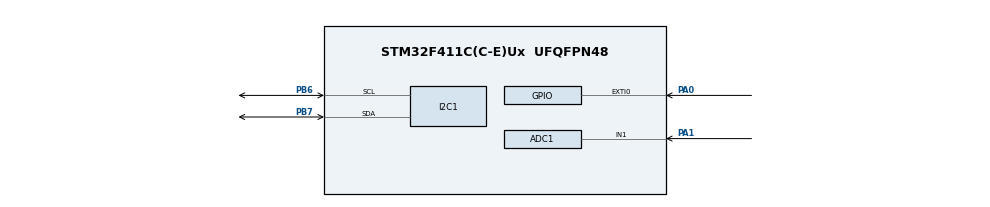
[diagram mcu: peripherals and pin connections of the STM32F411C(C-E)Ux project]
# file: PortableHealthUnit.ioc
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ADC1.Channel-0\#ChannelRegularConversion=ADC_CHANNEL_1
ADC1.NbrOfConversionFlag=1
ADC1.Rank-0\#ChannelRegularConversion=1
ADC1.SamplingTime-0\#ChannelRegularConversion=ADC_SAMPLETIME_3CYCLES
ADC1.master=1
Mcu.Family=STM32F4
Mcu.Name=STM32F411C(C-E)Ux
Mcu.Package=UFQFPN48
NVIC.PriorityGroup=NVIC_PRIORITYGROUP_4
PA0-WKUP.Signal=GPXTI0
PA1.Signal=ADCx_IN1
PB6.Mode=I2C
PB6.Signal=I2C1_SCL
PB7.Mode=I2C
PB7.Signal=I2C1_SDA
ProjectManager.HeapSize=0x200
ProjectManager.StackSize=0x400
ProjectManager.TargetToolchain=STM32CubeIDE
RCC.48MHZClocksFreq_Value=48000000
RCC.AHBFreq_Value=16000000
RCC.APB1Freq_Value=16000000
RCC.APB1TimFreq_Value=16000000
RCC.APB2Freq_Value=16000000
RCC.APB2TimFreq_Value=16000000
RCC.CortexFreq_Value=16000000
RCC.HCLKFreq_Value=16000000
RCC.HSE_VALUE=25000000
RCC.HSI_VALUE=16000000
RCC.LSE_VALUE=32768
RCC.SYSCLKFreq_VALUE=16000000
RCC.VCOOutputFreq_Value=192000000
SH.ADCx_IN1.0=ADC1_IN1,IN1
board=custom

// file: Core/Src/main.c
#include "main.h"
#include "i2c_lcd.h"
// #include "max30102.h" // MAX30102 header commented out
#include <stdio.h>

ADC_HandleTypeDef hadc1;
I2C_HandleTypeDef hi2c1;

// max30102_t max30102; // MAX30102 handle commented out

void SystemClock_Config(void);
static void MX_GPIO_Init(void);
static void MX_I2C1_Init(void);
static void MX_ADC1_Init(void);

int main(void)
{
  HAL_Init();
  SystemClock_Config();
  MX_GPIO_Init();
  MX_I2C1_Init();
  MX_ADC1_Init(); // Initialize the ADC

  lcd_init();
  // max30102_init(&max30102, &hi2c1); // MAX30102 init commented out

  lcd_clear();
  lcd_send_string("Reading Temp...");

  // char hr_str[20];     // MAX30102 string commented out
  // char spo2_str[20];   // MAX30102 string commented out
  char temp_str[20];

  uint32_t adc_value;
  float temperature_c;

  while (1)
  {
    // --- Read Temperature from LM35 ---
    HAL_ADC_Start(&hadc1);
    if (HAL_ADC_PollForConversion(&hadc1, 1000) == HAL_OK)
    {
        adc_value = HAL_ADC_GetValue(&hadc1);
        // Convert ADC value to voltage (assuming V_REF = 3.3V, ADC is 12-bit)
        // Then convert voltage to temperature (LM35 is 10mV/°C)
        temperature_c = ((float)adc_value / 4095.0) * 330.0;
    }tht
    HAL_ADC_Stop(&hadc1);

    // --- MAX30102 reading logic commented out ---
    // max30102_read_fifo(&max30102);
    // max30102_update(&max30102);

    // --- Update the LCD Display ---
    lcd_clear();

    // --- Displaying HR and SpO2 commented out ---
    /*
    sprintf(hr_str, "HR: %.0f BPM", max30102.heart_rate);
    sprintf(spo2_str, "SpO2: %.0f %%", max30102.spO2);
    lcd_put_cur(0, 0);
    lcd_send_string(hr_str);
    lcd_put_cur(1, 0);
    lcd_send_string(spo2_str);
    */

    // Format and display Temperature
    sprintf(temp_str, "Temp: %.2f C", temperature_c);
    lcd_put_cur(0, 0); // Display on the first line
    lcd_send_string(temp_str);

    HAL_Delay(1000); // Update display every second
  }
}

// ... (Your SystemClock_Config, MX_GPIO_Init, and MX_I2C1_Init functions) ...

static void MX_ADC1_Init(void)
{
  ADC_ChannelConfTypeDef sConfig = {0};

  hadc1.Instance = ADC1;
  hadc1.Init.ClockPrescaler = ADC_CLOCK_SYNC_PCLK_DIV4;
  hadc1.Init.Resolution = ADC_RESOLUTION_12B;
  hadc1.Init.ScanConvMode = DISABLE;
  hadc1.Init.ContinuousConvMode = DISABLE;
  hadc1.Init.DiscontinuousConvMode = DISABLE;
  hadc1.Init.ExternalTrigConvEdge = ADC_EXTERNALTRIGCONVEDGE_NONE;
  hadc1.Init.ExternalTrigConv = ADC_SOFTWARE_START;
  hadc1.Init.DataAlign = ADC_DATAALIGN_RIGHT;
  hadc1.Init.NbrOfConversion = 1;
  hadc1.Init.DMAContinuousRequests = DISABLE;
  hadc1.Init.EOCSelection = ADC_EOC_SINGLE_CONV;
  if (HAL_ADC_Init(&hadc1) != HAL_OK)
  {
    Error_Handler();
  }

  sConfig.Channel = ADC_CHANNEL_1;
  sConfig.Rank = 1;
  sConfig.SamplingTime = ADC_SAMPLETIME_3CYCLES;
  if (HAL_ADC_ConfigChannel(&hadc1, &sConfig) != HAL_OK)
  {
    Error_Handler();
  }
}

void SystemClock_Config(void)
{
  RCC_OscInitTypeDef RCC_OscInitStruct = {0};
  RCC_ClkInitTypeDef RCC_ClkInitStruct = {0};

  /** Configure the main internal regulator output voltage
  */
  __HAL_RCC_PWR_CLK_ENABLE();
  __HAL_PWR_VOLTAGESCALING_CONFIG(PWR_REGULATOR_VOLTAGE_SCALE1);

  /** Initializes the RCC Oscillators according to the specified parameters
  * in the RCC_OscInitTypeDef structure.
  */
  RCC_OscInitStruct.OscillatorType = RCC_OSCILLATORTYPE_HSE;
  RCC_OscInitStruct.HSEState = RCC_HSE_ON;
  RCC_OscInitStruct.PLL.PLLState = RCC_PLL_ON;
  RCC_OscInitStruct.PLL.PLLSource = RCC_PLLSOURCE_HSE;
  RCC_OscInitStruct.PLL.PLLM = 8;
  RCC_OscInitStruct.PLL.PLLN = 100;
  RCC_OscInitStruct.PLL.PLLP = RCC_PLLP_DIV2;
  RCC_OscInitStruct.PLL.PLLQ = 4;
  if (HAL_RCC_OscConfig(&RCC_OscInitStruct) != HAL_OK)
  {
    Error_Handler();
  }

  /** Initializes the CPU, AHB and APB buses clocks
  */
  RCC_ClkInitStruct.ClockType = RCC_CLOCKTYPE_HCLK|RCC_CLOCKTYPE_SYSCLK
                              |RCC_CLOCKTYPE_PCLK1|RCC_CLOCKTYPE_PCLK2;
  RCC_ClkInitStruct.SYSCLKSource = RCC_SYSCLKSOURCE_PLLCLK;
  RCC_ClkInitStruct.AHBCLKDivider = RCC_SYSCLK_DIV1;
  RCC_ClkInitStruct.APB1CLKDivider = RCC_HCLK_DIV2;
  RCC_ClkInitStruct.APB2CLKDivider = RCC_HCLK_DIV1;

  if (HAL_RCC_ClockConfig(&RCC_ClkInitStruct, FLASH_LATENCY_3) != HAL_OK)
  {
    Error_Handler();
  }
}

static void MX_I2C1_Init(void)
{
  hi2c1.Instance = I2C1;
  hi2c1.Init.ClockSpeed = 100000;
  hi2c1.Init.DutyCycle = I2C_DUTYCYCLE_2;
  hi2c1.Init.OwnAddress1 = 0;
  hi2c1.Init.AddressingMode = I2C_ADDRESSINGMODE_7BIT;
  hi2c1.Init.DualAddressMode = I2C_DUALADDRESS_DISABLE;
  hi2c1.Init.OwnAddress2 = 0;
  hi2c1.Init.GeneralCallMode = I2C_GENERALCALL_DISABLE;
  hi2c1.Init.NoStretchMode = I2C_NOSTRETCH_DISABLE;
  if (HAL_I2C_Init(&hi2c1) != HAL_OK)
  {
    Error_Handler();
  }
}

static void MX_GPIO_Init(void)
{
  /* GPIO Ports Clock Enable */
  __HAL_RCC_GPIOH_CLK_ENABLE();
  __HAL_RCC_GPIOA_CLK_ENABLE();
  __HAL_RCC_GPIOB_CLK_ENABLE();
}

void Error_Handler(void)
{
  __disable_irq();
  while (1)
  {
  }
}
